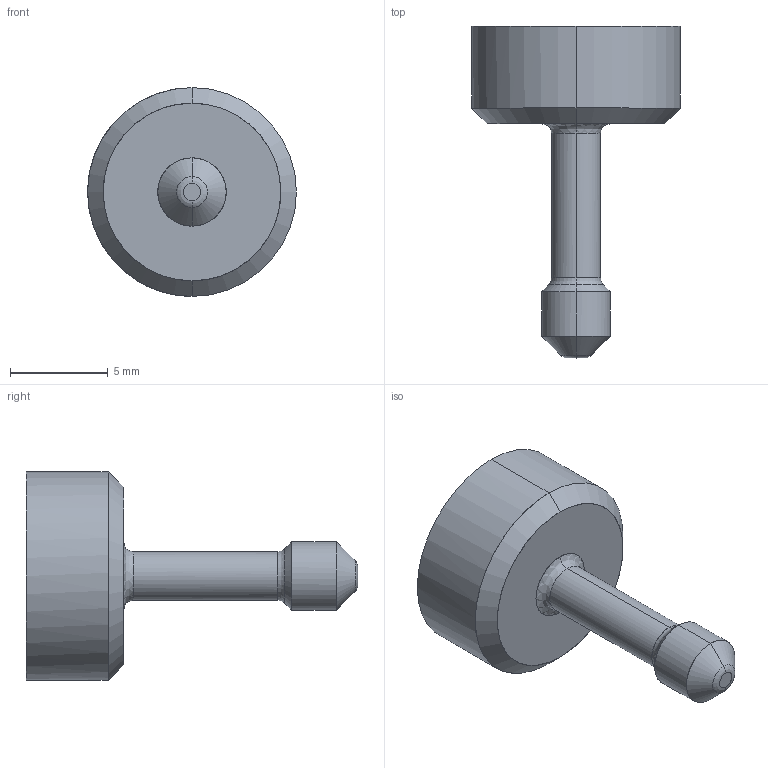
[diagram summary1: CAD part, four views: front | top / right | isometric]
IGES file: header records copied from the file, then geometry measured from it (millimetres).
Start section: START RECORD GO HERE.
Global section: file name: ia1007sf.igs; native system: DASSAULT SYSTEMES CATIA V5 R20 - www.3ds.com; preprocessor: CATIA Version 5 Release 20 ; author: Utente; organization: NB04-ASUS; date: 20201108.074546; units: millimetre
Bounding box: 10.7 x 17 x 10.7 mm (x, y, z)
Surface area: 446.6 mm2 (no closed solid volume)
Topology: 0 solids, 0 shells, 34 faces, 152 edges, 152 vertices
Faces by surface type: revolution 24, plane 10
